VERSION 5.7 ;
  NOWIREEXTENSIONATPIN ON ;
  DIVIDERCHAR "/" ;
  BUSBITCHARS "[]" ;
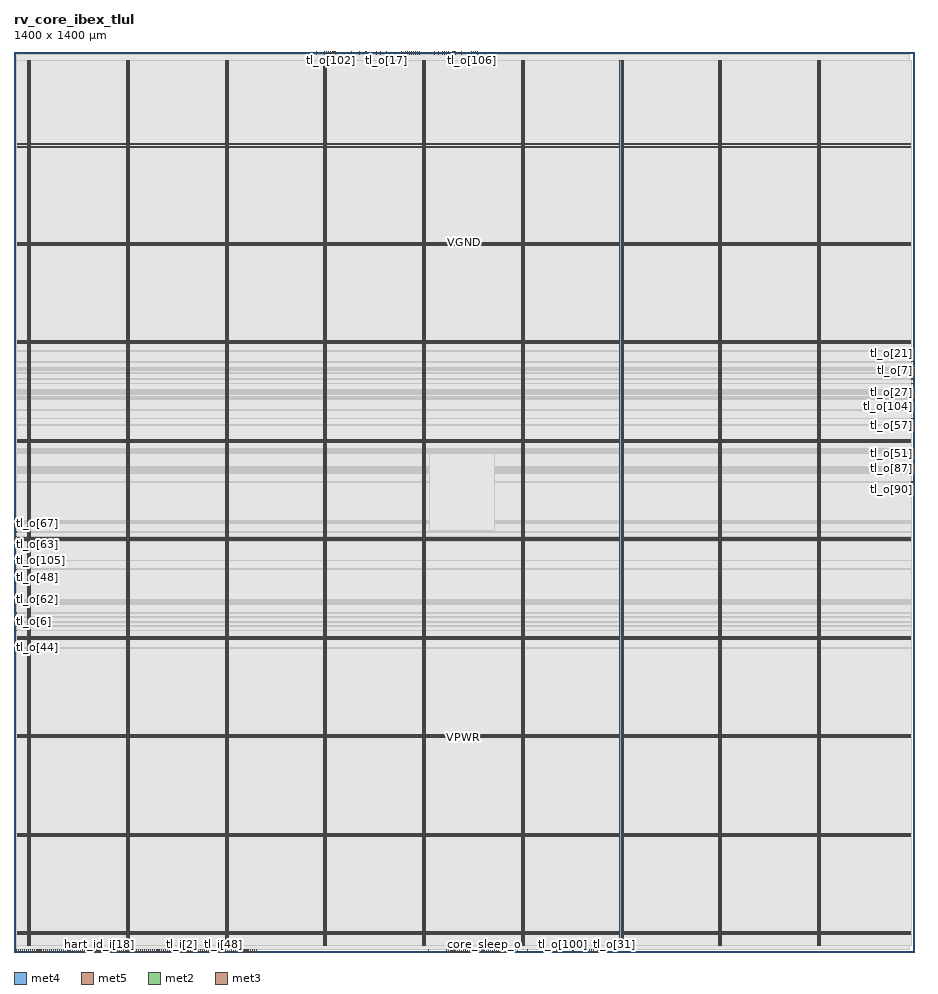
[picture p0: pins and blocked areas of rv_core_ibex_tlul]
MACRO rv_core_ibex_tlul
  CLASS BLOCK ;
  FOREIGN rv_core_ibex_tlul ;
  ORIGIN 0.000 0.000 ;
  SIZE 1400.000 BY 1400.000 ;
  PIN VGND
    DIRECTION INOUT ;
    USE GROUND ;
    PORT
      LAYER met4 ;
        RECT 24.340 10.640 25.940 1387.440 ;
    END
    PORT
      LAYER met4 ;
        RECT 177.940 10.640 179.540 1387.440 ;
    END
    PORT
      LAYER met4 ;
        RECT 331.540 10.640 333.140 1387.440 ;
    END
    PORT
      LAYER met4 ;
        RECT 485.140 10.640 486.740 1387.440 ;
    END
    PORT
      LAYER met4 ;
        RECT 638.740 10.640 640.340 1387.440 ;
    END
    PORT
      LAYER met4 ;
        RECT 792.340 10.640 793.940 1387.440 ;
    END
    PORT
      LAYER met4 ;
        RECT 945.940 10.640 947.540 1387.440 ;
    END
    PORT
      LAYER met4 ;
        RECT 1099.540 10.640 1101.140 1387.440 ;
    END
    PORT
      LAYER met4 ;
        RECT 1253.140 10.640 1254.740 1387.440 ;
    END
    PORT
      LAYER met5 ;
        RECT 5.280 30.030 1394.500 31.630 ;
    END
    PORT
      LAYER met5 ;
        RECT 5.280 183.210 1394.500 184.810 ;
    END
    PORT
      LAYER met5 ;
        RECT 5.280 336.390 1394.500 337.990 ;
    END
    PORT
      LAYER met5 ;
        RECT 5.280 489.570 1394.500 491.170 ;
    END
    PORT
      LAYER met5 ;
        RECT 5.280 642.750 1394.500 644.350 ;
    END
    PORT
      LAYER met5 ;
        RECT 5.280 795.930 1394.500 797.530 ;
    END
    PORT
      LAYER met5 ;
        RECT 5.280 949.110 1394.500 950.710 ;
    END
    PORT
      LAYER met5 ;
        RECT 5.280 1102.290 1394.500 1103.890 ;
    END
    PORT
      LAYER met5 ;
        RECT 5.280 1255.470 1394.500 1257.070 ;
    END
  END VGND
  PIN VPWR
    DIRECTION INOUT ;
    USE POWER ;
    PORT
      LAYER met4 ;
        RECT 21.040 10.640 22.640 1387.440 ;
    END
    PORT
      LAYER met4 ;
        RECT 174.640 10.640 176.240 1387.440 ;
    END
    PORT
      LAYER met4 ;
        RECT 328.240 10.640 329.840 1387.440 ;
    END
    PORT
      LAYER met4 ;
        RECT 481.840 10.640 483.440 1387.440 ;
    END
    PORT
      LAYER met4 ;
        RECT 635.440 10.640 637.040 1387.440 ;
    END
    PORT
      LAYER met4 ;
        RECT 789.040 10.640 790.640 1387.440 ;
    END
    PORT
      LAYER met4 ;
        RECT 942.640 10.640 944.240 1387.440 ;
    END
    PORT
      LAYER met4 ;
        RECT 1096.240 10.640 1097.840 1387.440 ;
    END
    PORT
      LAYER met4 ;
        RECT 1249.840 10.640 1251.440 1387.440 ;
    END
    PORT
      LAYER met5 ;
        RECT 5.280 26.730 1394.500 28.330 ;
    END
    PORT
      LAYER met5 ;
        RECT 5.280 179.910 1394.500 181.510 ;
    END
    PORT
      LAYER met5 ;
        RECT 5.280 333.090 1394.500 334.690 ;
    END
    PORT
      LAYER met5 ;
        RECT 5.280 486.270 1394.500 487.870 ;
    END
    PORT
      LAYER met5 ;
        RECT 5.280 639.450 1394.500 641.050 ;
    END
    PORT
      LAYER met5 ;
        RECT 5.280 792.630 1394.500 794.230 ;
    END
    PORT
      LAYER met5 ;
        RECT 5.280 945.810 1394.500 947.410 ;
    END
    PORT
      LAYER met5 ;
        RECT 5.280 1098.990 1394.500 1100.590 ;
    END
    PORT
      LAYER met5 ;
        RECT 5.280 1252.170 1394.500 1253.770 ;
    END
  END VPWR
  PIN boot_addr_i[0]
    DIRECTION INPUT ;
    USE SIGNAL ;
    PORT
      LAYER met2 ;
        RECT 0.090 0.000 0.370 4.000 ;
    END
  END boot_addr_i[0]
  PIN boot_addr_i[10]
    DIRECTION INPUT ;
    USE SIGNAL ;
    PORT
      LAYER met2 ;
        RECT 3.310 0.000 3.590 4.000 ;
    END
  END boot_addr_i[10]
  PIN boot_addr_i[11]
    DIRECTION INPUT ;
    USE SIGNAL ;
    PORT
      LAYER met2 ;
        RECT 6.530 0.000 6.810 4.000 ;
    END
  END boot_addr_i[11]
  PIN boot_addr_i[12]
    DIRECTION INPUT ;
    USE SIGNAL ;
    PORT
      LAYER met2 ;
        RECT 9.750 0.000 10.030 4.000 ;
    END
  END boot_addr_i[12]
  PIN boot_addr_i[13]
    DIRECTION INPUT ;
    USE SIGNAL ;
    PORT
      LAYER met2 ;
        RECT 12.970 0.000 13.250 4.000 ;
    END
  END boot_addr_i[13]
  PIN boot_addr_i[14]
    DIRECTION INPUT ;
    USE SIGNAL ;
    PORT
      LAYER met2 ;
        RECT 16.190 0.000 16.470 4.000 ;
    END
  END boot_addr_i[14]
  PIN boot_addr_i[15]
    DIRECTION INPUT ;
    USE SIGNAL ;
    PORT
      LAYER met2 ;
        RECT 19.410 0.000 19.690 4.000 ;
    END
  END boot_addr_i[15]
  PIN boot_addr_i[16]
    DIRECTION INPUT ;
    USE SIGNAL ;
    PORT
      LAYER met2 ;
        RECT 22.630 0.000 22.910 4.000 ;
    END
  END boot_addr_i[16]
  PIN boot_addr_i[17]
    DIRECTION INPUT ;
    USE SIGNAL ;
    PORT
      LAYER met2 ;
        RECT 25.850 0.000 26.130 4.000 ;
    END
  END boot_addr_i[17]
  PIN boot_addr_i[18]
    DIRECTION INPUT ;
    USE SIGNAL ;
    PORT
      LAYER met2 ;
        RECT 29.070 0.000 29.350 4.000 ;
    END
  END boot_addr_i[18]
  PIN boot_addr_i[19]
    DIRECTION INPUT ;
    USE SIGNAL ;
    PORT
      LAYER met2 ;
        RECT 32.290 0.000 32.570 4.000 ;
    END
  END boot_addr_i[19]
  PIN boot_addr_i[1]
    DIRECTION INPUT ;
    USE SIGNAL ;
    PORT
      LAYER met2 ;
        RECT 35.510 0.000 35.790 4.000 ;
    END
  END boot_addr_i[1]
  PIN boot_addr_i[20]
    DIRECTION INPUT ;
    USE SIGNAL ;
    PORT
      LAYER met2 ;
        RECT 38.730 0.000 39.010 4.000 ;
    END
  END boot_addr_i[20]
  PIN boot_addr_i[21]
    DIRECTION INPUT ;
    USE SIGNAL ;
    PORT
      LAYER met2 ;
        RECT 41.950 0.000 42.230 4.000 ;
    END
  END boot_addr_i[21]
  PIN boot_addr_i[22]
    DIRECTION INPUT ;
    USE SIGNAL ;
    PORT
      LAYER met2 ;
        RECT 45.170 0.000 45.450 4.000 ;
    END
  END boot_addr_i[22]
  PIN boot_addr_i[23]
    DIRECTION INPUT ;
    USE SIGNAL ;
    PORT
      LAYER met2 ;
        RECT 48.390 0.000 48.670 4.000 ;
    END
  END boot_addr_i[23]
  PIN boot_addr_i[24]
    DIRECTION INPUT ;
    USE SIGNAL ;
    PORT
      LAYER met2 ;
        RECT 51.610 0.000 51.890 4.000 ;
    END
  END boot_addr_i[24]
  PIN boot_addr_i[25]
    DIRECTION INPUT ;
    USE SIGNAL ;
    PORT
      LAYER met2 ;
        RECT 54.830 0.000 55.110 4.000 ;
    END
  END boot_addr_i[25]
  PIN boot_addr_i[26]
    DIRECTION INPUT ;
    USE SIGNAL ;
    PORT
      LAYER met2 ;
        RECT 58.050 0.000 58.330 4.000 ;
    END
  END boot_addr_i[26]
  PIN boot_addr_i[27]
    DIRECTION INPUT ;
    USE SIGNAL ;
    PORT
      LAYER met2 ;
        RECT 61.270 0.000 61.550 4.000 ;
    END
  END boot_addr_i[27]
  PIN boot_addr_i[28]
    DIRECTION INPUT ;
    USE SIGNAL ;
    PORT
      LAYER met2 ;
        RECT 64.490 0.000 64.770 4.000 ;
    END
  END boot_addr_i[28]
  PIN boot_addr_i[29]
    DIRECTION INPUT ;
    USE SIGNAL ;
    PORT
      LAYER met2 ;
        RECT 67.710 0.000 67.990 4.000 ;
    END
  END boot_addr_i[29]
  PIN boot_addr_i[2]
    DIRECTION INPUT ;
    USE SIGNAL ;
    PORT
      LAYER met2 ;
        RECT 70.930 0.000 71.210 4.000 ;
    END
  END boot_addr_i[2]
  PIN boot_addr_i[30]
    DIRECTION INPUT ;
    USE SIGNAL ;
    PORT
      LAYER met2 ;
        RECT 74.150 0.000 74.430 4.000 ;
    END
  END boot_addr_i[30]
  PIN boot_addr_i[31]
    DIRECTION INPUT ;
    USE SIGNAL ;
    PORT
      LAYER met2 ;
        RECT 77.370 0.000 77.650 4.000 ;
    END
  END boot_addr_i[31]
  PIN boot_addr_i[3]
    DIRECTION INPUT ;
    USE SIGNAL ;
    PORT
      LAYER met2 ;
        RECT 80.590 0.000 80.870 4.000 ;
    END
  END boot_addr_i[3]
  PIN boot_addr_i[4]
    DIRECTION INPUT ;
    USE SIGNAL ;
    PORT
      LAYER met2 ;
        RECT 83.810 0.000 84.090 4.000 ;
    END
  END boot_addr_i[4]
  PIN boot_addr_i[5]
    DIRECTION INPUT ;
    USE SIGNAL ;
    PORT
      LAYER met2 ;
        RECT 87.030 0.000 87.310 4.000 ;
    END
  END boot_addr_i[5]
  PIN boot_addr_i[6]
    DIRECTION INPUT ;
    USE SIGNAL ;
    PORT
      LAYER met2 ;
        RECT 90.250 0.000 90.530 4.000 ;
    END
  END boot_addr_i[6]
  PIN boot_addr_i[7]
    DIRECTION INPUT ;
    USE SIGNAL ;
    PORT
      LAYER met2 ;
        RECT 93.470 0.000 93.750 4.000 ;
    END
  END boot_addr_i[7]
  PIN boot_addr_i[8]
    DIRECTION INPUT ;
    USE SIGNAL ;
    PORT
      LAYER met2 ;
        RECT 96.690 0.000 96.970 4.000 ;
    END
  END boot_addr_i[8]
  PIN boot_addr_i[9]
    DIRECTION INPUT ;
    USE SIGNAL ;
    PORT
      LAYER met2 ;
        RECT 99.910 0.000 100.190 4.000 ;
    END
  END boot_addr_i[9]
  PIN clk_i
    DIRECTION INPUT ;
    USE SIGNAL ;
    ANTENNAGATEAREA 1.286700 ;
    ANTENNADIFFAREA 0.434700 ;
    PORT
      LAYER met2 ;
        RECT 782.550 0.000 782.830 4.000 ;
    END
  END clk_i
  PIN core_sleep_o
    DIRECTION OUTPUT ;
    USE SIGNAL ;
    ANTENNADIFFAREA 0.445500 ;
    PORT
      LAYER met2 ;
        RECT 731.030 0.000 731.310 4.000 ;
    END
  END core_sleep_o
  PIN hart_id_i[0]
    DIRECTION INPUT ;
    USE SIGNAL ;
    PORT
      LAYER met2 ;
        RECT 103.130 0.000 103.410 4.000 ;
    END
  END hart_id_i[0]
  PIN hart_id_i[10]
    DIRECTION INPUT ;
    USE SIGNAL ;
    PORT
      LAYER met2 ;
        RECT 106.350 0.000 106.630 4.000 ;
    END
  END hart_id_i[10]
  PIN hart_id_i[11]
    DIRECTION INPUT ;
    USE SIGNAL ;
    PORT
      LAYER met2 ;
        RECT 109.570 0.000 109.850 4.000 ;
    END
  END hart_id_i[11]
  PIN hart_id_i[12]
    DIRECTION INPUT ;
    USE SIGNAL ;
    PORT
      LAYER met2 ;
        RECT 112.790 0.000 113.070 4.000 ;
    END
  END hart_id_i[12]
  PIN hart_id_i[13]
    DIRECTION INPUT ;
    USE SIGNAL ;
    PORT
      LAYER met2 ;
        RECT 116.010 0.000 116.290 4.000 ;
    END
  END hart_id_i[13]
  PIN hart_id_i[14]
    DIRECTION INPUT ;
    USE SIGNAL ;
    PORT
      LAYER met2 ;
        RECT 119.230 0.000 119.510 4.000 ;
    END
  END hart_id_i[14]
  PIN hart_id_i[15]
    DIRECTION INPUT ;
    USE SIGNAL ;
    PORT
      LAYER met2 ;
        RECT 122.450 0.000 122.730 4.000 ;
    END
  END hart_id_i[15]
  PIN hart_id_i[16]
    DIRECTION INPUT ;
    USE SIGNAL ;
    PORT
      LAYER met2 ;
        RECT 125.670 0.000 125.950 4.000 ;
    END
  END hart_id_i[16]
  PIN hart_id_i[17]
    DIRECTION INPUT ;
    USE SIGNAL ;
    PORT
      LAYER met2 ;
        RECT 128.890 0.000 129.170 4.000 ;
    END
  END hart_id_i[17]
  PIN hart_id_i[18]
    DIRECTION INPUT ;
    USE SIGNAL ;
    PORT
      LAYER met2 ;
        RECT 132.110 0.000 132.390 4.000 ;
    END
  END hart_id_i[18]
  PIN hart_id_i[19]
    DIRECTION INPUT ;
    USE SIGNAL ;
    PORT
      LAYER met2 ;
        RECT 135.330 0.000 135.610 4.000 ;
    END
  END hart_id_i[19]
  PIN hart_id_i[1]
    DIRECTION INPUT ;
    USE SIGNAL ;
    PORT
      LAYER met2 ;
        RECT 138.550 0.000 138.830 4.000 ;
    END
  END hart_id_i[1]
  PIN hart_id_i[20]
    DIRECTION INPUT ;
    USE SIGNAL ;
    PORT
      LAYER met2 ;
        RECT 141.770 0.000 142.050 4.000 ;
    END
  END hart_id_i[20]
  PIN hart_id_i[21]
    DIRECTION INPUT ;
    USE SIGNAL ;
    PORT
      LAYER met2 ;
        RECT 144.990 0.000 145.270 4.000 ;
    END
  END hart_id_i[21]
  PIN hart_id_i[22]
    DIRECTION INPUT ;
    USE SIGNAL ;
    PORT
      LAYER met2 ;
        RECT 148.210 0.000 148.490 4.000 ;
    END
  END hart_id_i[22]
  PIN hart_id_i[23]
    DIRECTION INPUT ;
    USE SIGNAL ;
    PORT
      LAYER met2 ;
        RECT 151.430 0.000 151.710 4.000 ;
    END
  END hart_id_i[23]
  PIN hart_id_i[24]
    DIRECTION INPUT ;
    USE SIGNAL ;
    PORT
      LAYER met2 ;
        RECT 154.650 0.000 154.930 4.000 ;
    END
  END hart_id_i[24]
  PIN hart_id_i[25]
    DIRECTION INPUT ;
    USE SIGNAL ;
    PORT
      LAYER met2 ;
        RECT 157.870 0.000 158.150 4.000 ;
    END
  END hart_id_i[25]
  PIN hart_id_i[26]
    DIRECTION INPUT ;
    USE SIGNAL ;
    PORT
      LAYER met2 ;
        RECT 161.090 0.000 161.370 4.000 ;
    END
  END hart_id_i[26]
  PIN hart_id_i[27]
    DIRECTION INPUT ;
    USE SIGNAL ;
    PORT
      LAYER met2 ;
        RECT 164.310 0.000 164.590 4.000 ;
    END
  END hart_id_i[27]
  PIN hart_id_i[28]
    DIRECTION INPUT ;
    USE SIGNAL ;
    PORT
      LAYER met2 ;
        RECT 167.530 0.000 167.810 4.000 ;
    END
  END hart_id_i[28]
  PIN hart_id_i[29]
    DIRECTION INPUT ;
    USE SIGNAL ;
    PORT
      LAYER met2 ;
        RECT 170.750 0.000 171.030 4.000 ;
    END
  END hart_id_i[29]
  PIN hart_id_i[2]
    DIRECTION INPUT ;
    USE SIGNAL ;
    PORT
      LAYER met2 ;
        RECT 173.970 0.000 174.250 4.000 ;
    END
  END hart_id_i[2]
  PIN hart_id_i[30]
    DIRECTION INPUT ;
    USE SIGNAL ;
    PORT
      LAYER met2 ;
        RECT 177.190 0.000 177.470 4.000 ;
    END
  END hart_id_i[30]
  PIN hart_id_i[31]
    DIRECTION INPUT ;
    USE SIGNAL ;
    PORT
      LAYER met2 ;
        RECT 180.410 0.000 180.690 4.000 ;
    END
  END hart_id_i[31]
  PIN hart_id_i[3]
    DIRECTION INPUT ;
    USE SIGNAL ;
    PORT
      LAYER met2 ;
        RECT 183.630 0.000 183.910 4.000 ;
    END
  END hart_id_i[3]
  PIN hart_id_i[4]
    DIRECTION INPUT ;
    USE SIGNAL ;
    PORT
      LAYER met2 ;
        RECT 186.850 0.000 187.130 4.000 ;
    END
  END hart_id_i[4]
  PIN hart_id_i[5]
    DIRECTION INPUT ;
    USE SIGNAL ;
    PORT
      LAYER met2 ;
        RECT 190.070 0.000 190.350 4.000 ;
    END
  END hart_id_i[5]
  PIN hart_id_i[6]
    DIRECTION INPUT ;
    USE SIGNAL ;
    PORT
      LAYER met2 ;
        RECT 193.290 0.000 193.570 4.000 ;
    END
  END hart_id_i[6]
  PIN hart_id_i[7]
    DIRECTION INPUT ;
    USE SIGNAL ;
    PORT
      LAYER met2 ;
        RECT 196.510 0.000 196.790 4.000 ;
    END
  END hart_id_i[7]
  PIN hart_id_i[8]
    DIRECTION INPUT ;
    USE SIGNAL ;
    PORT
      LAYER met2 ;
        RECT 199.730 0.000 200.010 4.000 ;
    END
  END hart_id_i[8]
  PIN hart_id_i[9]
    DIRECTION INPUT ;
    USE SIGNAL ;
    PORT
      LAYER met2 ;
        RECT 202.950 0.000 203.230 4.000 ;
    END
  END hart_id_i[9]
  PIN irq_external_i
    DIRECTION INPUT ;
    USE SIGNAL ;
    PORT
      LAYER met2 ;
        RECT 206.170 0.000 206.450 4.000 ;
    END
  END irq_external_i
  PIN irq_software_i
    DIRECTION INPUT ;
    USE SIGNAL ;
    PORT
      LAYER met2 ;
        RECT 209.390 0.000 209.670 4.000 ;
    END
  END irq_software_i
  PIN irq_timer_i
    DIRECTION INPUT ;
    USE SIGNAL ;
    PORT
      LAYER met2 ;
        RECT 212.610 0.000 212.890 4.000 ;
    END
  END irq_timer_i
  PIN rst_ni
    DIRECTION INPUT ;
    USE SIGNAL ;
    ANTENNAGATEAREA 0.682200 ;
    ANTENNADIFFAREA 0.434700 ;
    PORT
      LAYER met2 ;
        RECT 644.090 0.000 644.370 4.000 ;
    END
  END rst_ni
  PIN tl_i[0]
    DIRECTION INPUT ;
    USE SIGNAL ;
    ANTENNAGATEAREA 0.682200 ;
    ANTENNADIFFAREA 0.434700 ;
    PORT
      LAYER met2 ;
        RECT 679.510 0.000 679.790 4.000 ;
    END
  END tl_i[0]
  PIN tl_i[10]
    DIRECTION INPUT ;
    USE SIGNAL ;
    ANTENNAGATEAREA 0.631200 ;
    ANTENNADIFFAREA 0.434700 ;
    PORT
      LAYER met2 ;
        RECT 698.830 0.000 699.110 4.000 ;
    END
  END tl_i[10]
  PIN tl_i[11]
    DIRECTION INPUT ;
    USE SIGNAL ;
    ANTENNAGATEAREA 0.631200 ;
    ANTENNADIFFAREA 0.434700 ;
    PORT
      LAYER met2 ;
        RECT 714.930 0.000 715.210 4.000 ;
    END
  END tl_i[11]
  PIN tl_i[12]
    DIRECTION INPUT ;
    USE SIGNAL ;
    ANTENNAGATEAREA 0.631200 ;
    ANTENNADIFFAREA 0.434700 ;
    PORT
      LAYER met2 ;
        RECT 705.270 0.000 705.550 4.000 ;
    END
  END tl_i[12]
  PIN tl_i[13]
    DIRECTION INPUT ;
    USE SIGNAL ;
    ANTENNAGATEAREA 0.631200 ;
    ANTENNADIFFAREA 0.434700 ;
    PORT
      LAYER met2 ;
        RECT 727.810 0.000 728.090 4.000 ;
    END
  END tl_i[13]
  PIN tl_i[14]
    DIRECTION INPUT ;
    USE SIGNAL ;
    ANTENNAGATEAREA 0.631200 ;
    ANTENNADIFFAREA 0.434700 ;
    PORT
      LAYER met2 ;
        RECT 779.330 0.000 779.610 4.000 ;
    END
  END tl_i[14]
  PIN tl_i[15]
    DIRECTION INPUT ;
    USE SIGNAL ;
    ANTENNAGATEAREA 0.631200 ;
    ANTENNADIFFAREA 0.434700 ;
    PORT
      LAYER met2 ;
        RECT 743.910 0.000 744.190 4.000 ;
    END
  END tl_i[15]
  PIN tl_i[16]
    DIRECTION INPUT ;
    USE SIGNAL ;
    PORT
      LAYER met2 ;
        RECT 215.830 0.000 216.110 4.000 ;
    END
  END tl_i[16]
  PIN tl_i[17]
    DIRECTION INPUT ;
    USE SIGNAL ;
    PORT
      LAYER met2 ;
        RECT 219.050 0.000 219.330 4.000 ;
    END
  END tl_i[17]
  PIN tl_i[18]
    DIRECTION INPUT ;
    USE SIGNAL ;
    PORT
      LAYER met2 ;
        RECT 222.270 0.000 222.550 4.000 ;
    END
  END tl_i[18]
  PIN tl_i[19]
    DIRECTION INPUT ;
    USE SIGNAL ;
    PORT
      LAYER met2 ;
        RECT 225.490 0.000 225.770 4.000 ;
    END
  END tl_i[19]
  PIN tl_i[1]
    DIRECTION INPUT ;
    USE SIGNAL ;
    ANTENNAGATEAREA 0.860700 ;
    ANTENNADIFFAREA 0.434700 ;
    PORT
      LAYER met2 ;
        RECT 718.150 0.000 718.430 4.000 ;
    END
  END tl_i[1]
  PIN tl_i[20]
    DIRECTION INPUT ;
    USE SIGNAL ;
    PORT
      LAYER met2 ;
        RECT 228.710 0.000 228.990 4.000 ;
    END
  END tl_i[20]
  PIN tl_i[21]
    DIRECTION INPUT ;
    USE SIGNAL ;
    PORT
      LAYER met2 ;
        RECT 231.930 0.000 232.210 4.000 ;
    END
  END tl_i[21]
  PIN tl_i[22]
    DIRECTION INPUT ;
    USE SIGNAL ;
    PORT
      LAYER met2 ;
        RECT 235.150 0.000 235.430 4.000 ;
    END
  END tl_i[22]
  PIN tl_i[23]
    DIRECTION INPUT ;
    USE SIGNAL ;
    PORT
      LAYER met2 ;
        RECT 238.370 0.000 238.650 4.000 ;
    END
  END tl_i[23]
  PIN tl_i[24]
    DIRECTION INPUT ;
    USE SIGNAL ;
    PORT
      LAYER met2 ;
        RECT 241.590 0.000 241.870 4.000 ;
    END
  END tl_i[24]
  PIN tl_i[25]
    DIRECTION INPUT ;
    USE SIGNAL ;
    PORT
      LAYER met2 ;
        RECT 244.810 0.000 245.090 4.000 ;
    END
  END tl_i[25]
  PIN tl_i[26]
    DIRECTION INPUT ;
    USE SIGNAL ;
    PORT
      LAYER met2 ;
        RECT 248.030 0.000 248.310 4.000 ;
    END
  END tl_i[26]
  PIN tl_i[27]
    DIRECTION INPUT ;
    USE SIGNAL ;
    PORT
      LAYER met2 ;
        RECT 251.250 0.000 251.530 4.000 ;
    END
  END tl_i[27]
  PIN tl_i[28]
    DIRECTION INPUT ;
    USE SIGNAL ;
    PORT
      LAYER met2 ;
        RECT 254.470 0.000 254.750 4.000 ;
    END
  END tl_i[28]
  PIN tl_i[29]
    DIRECTION INPUT ;
    USE SIGNAL ;
    PORT
      LAYER met2 ;
        RECT 257.690 0.000 257.970 4.000 ;
    END
  END tl_i[29]
  PIN tl_i[2]
    DIRECTION INPUT ;
    USE SIGNAL ;
    PORT
      LAYER met2 ;
        RECT 260.910 0.000 261.190 4.000 ;
    END
  END tl_i[2]
  PIN tl_i[30]
    DIRECTION INPUT ;
    USE SIGNAL ;
    PORT
      LAYER met2 ;
        RECT 264.130 0.000 264.410 4.000 ;
    END
  END tl_i[30]
  PIN tl_i[31]
    DIRECTION INPUT ;
    USE SIGNAL ;
    PORT
      LAYER met2 ;
        RECT 267.350 0.000 267.630 4.000 ;
    END
  END tl_i[31]
  PIN tl_i[32]
    DIRECTION INPUT ;
    USE SIGNAL ;
    PORT
      LAYER met2 ;
        RECT 270.570 0.000 270.850 4.000 ;
    END
  END tl_i[32]
  PIN tl_i[33]
    DIRECTION INPUT ;
    USE SIGNAL ;
    PORT
      LAYER met2 ;
        RECT 273.790 0.000 274.070 4.000 ;
    END
  END tl_i[33]
  PIN tl_i[34]
    DIRECTION INPUT ;
    USE SIGNAL ;
    PORT
      LAYER met2 ;
        RECT 277.010 0.000 277.290 4.000 ;
    END
  END tl_i[34]
  PIN tl_i[35]
    DIRECTION INPUT ;
    USE SIGNAL ;
    PORT
      LAYER met2 ;
        RECT 280.230 0.000 280.510 4.000 ;
    END
  END tl_i[35]
  PIN tl_i[36]
    DIRECTION INPUT ;
    USE SIGNAL ;
    PORT
      LAYER met2 ;
        RECT 283.450 0.000 283.730 4.000 ;
    END
  END tl_i[36]
  PIN tl_i[37]
    DIRECTION INPUT ;
    USE SIGNAL ;
    PORT
      LAYER met2 ;
        RECT 286.670 0.000 286.950 4.000 ;
    END
  END tl_i[37]
  PIN tl_i[38]
    DIRECTION INPUT ;
    USE SIGNAL ;
    PORT
      LAYER met2 ;
        RECT 289.890 0.000 290.170 4.000 ;
    END
  END tl_i[38]
  PIN tl_i[39]
    DIRECTION INPUT ;
    USE SIGNAL ;
    PORT
      LAYER met2 ;
        RECT 293.110 0.000 293.390 4.000 ;
    END
  END tl_i[39]
  PIN tl_i[3]
    DIRECTION INPUT ;
    USE SIGNAL ;
    PORT
      LAYER met2 ;
        RECT 296.330 0.000 296.610 4.000 ;
    END
  END tl_i[3]
  PIN tl_i[40]
    DIRECTION INPUT ;
    USE SIGNAL ;
    PORT
      LAYER met2 ;
        RECT 299.550 0.000 299.830 4.000 ;
    END
  END tl_i[40]
  PIN tl_i[41]
    DIRECTION INPUT ;
    USE SIGNAL ;
    PORT
      LAYER met2 ;
        RECT 302.770 0.000 303.050 4.000 ;
    END
  END tl_i[41]
  PIN tl_i[42]
    DIRECTION INPUT ;
    USE SIGNAL ;
    PORT
      LAYER met2 ;
        RECT 305.990 0.000 306.270 4.000 ;
    END
  END tl_i[42]
  PIN tl_i[43]
    DIRECTION INPUT ;
    USE SIGNAL ;
    PORT
      LAYER met2 ;
        RECT 309.210 0.000 309.490 4.000 ;
    END
  END tl_i[43]
  PIN tl_i[44]
    DIRECTION INPUT ;
    USE SIGNAL ;
    PORT
      LAYER met2 ;
        RECT 312.430 0.000 312.710 4.000 ;
    END
  END tl_i[44]
  PIN tl_i[45]
    DIRECTION INPUT ;
    USE SIGNAL ;
    PORT
      LAYER met2 ;
        RECT 315.650 0.000 315.930 4.000 ;
    END
  END tl_i[45]
  PIN tl_i[46]
    DIRECTION INPUT ;
    USE SIGNAL ;
    PORT
      LAYER met2 ;
        RECT 318.870 0.000 319.150 4.000 ;
    END
  END tl_i[46]
  PIN tl_i[47]
    DIRECTION INPUT ;
    USE SIGNAL ;
    PORT
      LAYER met2 ;
        RECT 322.090 0.000 322.370 4.000 ;
    END
  END tl_i[47]
  PIN tl_i[48]
    DIRECTION INPUT ;
    USE SIGNAL ;
    PORT
      LAYER met2 ;
        RECT 325.310 0.000 325.590 4.000 ;
    END
  END tl_i[48]
  PIN tl_i[49]
    DIRECTION INPUT ;
    USE SIGNAL ;
    PORT
      LAYER met2 ;
        RECT 328.530 0.000 328.810 4.000 ;
    END
  END tl_i[49]
  PIN tl_i[4]
    DIRECTION INPUT ;
    USE SIGNAL ;
    PORT
      LAYER met2 ;
        RECT 331.750 0.000 332.030 4.000 ;
    END
  END tl_i[4]
  PIN tl_i[50]
    DIRECTION INPUT ;
    USE SIGNAL ;
    PORT
      LAYER met2 ;
        RECT 334.970 0.000 335.250 4.000 ;
    END
  END tl_i[50]
  PIN tl_i[51]
    DIRECTION INPUT ;
    USE SIGNAL ;
    PORT
      LAYER met2 ;
        RECT 338.190 0.000 338.470 4.000 ;
    END
  END tl_i[51]
  PIN tl_i[52]
    DIRECTION INPUT ;
    USE SIGNAL ;
    PORT
      LAYER met2 ;
        RECT 341.410 0.000 341.690 4.000 ;
    END
  END tl_i[52]
  PIN tl_i[53]
    DIRECTION INPUT ;
    USE SIGNAL ;
    PORT
      LAYER met2 ;
        RECT 344.630 0.000 344.910 4.000 ;
    END
  END tl_i[53]
  PIN tl_i[54]
    DIRECTION INPUT ;
    USE SIGNAL ;
    PORT
      LAYER met2 ;
        RECT 347.850 0.000 348.130 4.000 ;
    END
  END tl_i[54]
  PIN tl_i[55]
    DIRECTION INPUT ;
    USE SIGNAL ;
    PORT
      LAYER met2 ;
        RECT 351.070 0.000 351.350 4.000 ;
    END
  END tl_i[55]
  PIN tl_i[56]
    DIRECTION INPUT ;
    USE SIGNAL ;
    PORT
      LAYER met2 ;
        RECT 354.290 0.000 354.570 4.000 ;
    END
  END tl_i[56]
  PIN tl_i[57]
    DIRECTION INPUT ;
    USE SIGNAL ;
    ANTENNAGATEAREA 0.631200 ;
    ANTENNADIFFAREA 0.434700 ;
    PORT
      LAYER met2 ;
        RECT 711.710 0.000 711.990 4.000 ;
    END
  END tl_i[57]
  PIN tl_i[58]
    DIRECTION INPUT ;
    USE SIGNAL ;
    ANTENNAGATEAREA 0.631200 ;
    ANTENNADIFFAREA 0.434700 ;
    PORT
      LAYER met2 ;
        RECT 734.250 0.000 734.530 4.000 ;
    END
  END tl_i[58]
  PIN tl_i[59]
    DIRECTION INPUT ;
    USE SIGNAL ;
    PORT
      LAYER met2 ;
        RECT 357.510 0.000 357.790 4.000 ;
    END
  END tl_i[59]
  PIN tl_i[5]
    DIRECTION INPUT ;
    USE SIGNAL ;
    PORT
      LAYER met2 ;
        RECT 360.730 0.000 361.010 4.000 ;
    END
  END tl_i[5]
  PIN tl_i[60]
    DIRECTION INPUT ;
    USE SIGNAL ;
    PORT
      LAYER met2 ;
        RECT 363.950 0.000 364.230 4.000 ;
    END
  END tl_i[60]
  PIN tl_i[61]
    DIRECTION INPUT ;
    USE SIGNAL ;
    PORT
      LAYER met2 ;
        RECT 367.170 0.000 367.450 4.000 ;
    END
  END tl_i[61]
  PIN tl_i[62]
    DIRECTION INPUT ;
    USE SIGNAL ;
    ANTENNAGATEAREA 0.560700 ;
    ANTENNADIFFAREA 0.434700 ;
    PORT
      LAYER met2 ;
        RECT 747.130 0.000 747.410 4.000 ;
    END
  END tl_i[62]
  PIN tl_i[63]
    DIRECTION INPUT ;
    USE SIGNAL ;
    ANTENNAGATEAREA 0.631200 ;
    ANTENNADIFFAREA 0.434700 ;
    PORT
      LAYER met2 ;
        RECT 737.470 0.000 737.750 4.000 ;
    END
  END tl_i[63]
  PIN tl_i[64]
    DIRECTION INPUT ;
    USE SIGNAL ;
    ANTENNAGATEAREA 0.560700 ;
    ANTENNADIFFAREA 0.434700 ;
    PORT
      LAYER met2 ;
        RECT 708.490 0.000 708.770 4.000 ;
    END
  END tl_i[64]
  PIN tl_i[65]
    DIRECTION INPUT ;
    USE SIGNAL ;
    ANTENNAGATEAREA 0.860700 ;
    ANTENNADIFFAREA 0.434700 ;
    PORT
      LAYER met2 ;
        RECT 692.390 0.000 692.670 4.000 ;
    END
  END tl_i[65]
  PIN tl_i[6]
    DIRECTION INPUT ;
    USE SIGNAL ;
    PORT
      LAYER met2 ;
        RECT 370.390 0.000 370.670 4.000 ;
    END
  END tl_i[6]
  PIN tl_i[7]
    DIRECTION INPUT ;
    USE SIGNAL ;
    PORT
      LAYER met2 ;
        RECT 373.610 0.000 373.890 4.000 ;
    END
  END tl_i[7]
  PIN tl_i[8]
    DIRECTION INPUT ;
    USE SIGNAL ;
    PORT
      LAYER met2 ;
        RECT 376.830 0.000 377.110 4.000 ;
    END
  END tl_i[8]
  PIN tl_i[9]
    DIRECTION INPUT ;
    USE SIGNAL ;
    ANTENNAGATEAREA 0.631200 ;
    ANTENNADIFFAREA 0.434700 ;
    PORT
      LAYER met2 ;
        RECT 702.050 0.000 702.330 4.000 ;
    END
  END tl_i[9]
  PIN tl_o[0]
    DIRECTION OUTPUT ;
    USE SIGNAL ;
    PORT
      LAYER met2 ;
        RECT 483.090 1396.000 483.370 1400.000 ;
    END
  END tl_o[0]
  PIN tl_o[100]
    DIRECTION OUTPUT ;
    USE SIGNAL ;
    PORT
      LAYER met2 ;
        RECT 853.390 0.000 853.670 4.000 ;
    END
  END tl_o[100]
  PIN tl_o[101]
    DIRECTION OUTPUT ;
    USE SIGNAL ;
    PORT
      LAYER met2 ;
        RECT 682.730 0.000 683.010 4.000 ;
    END
  END tl_o[101]
  PIN tl_o[102]
    DIRECTION OUTPUT ;
    USE SIGNAL ;
    PORT
      LAYER met2 ;
        RECT 492.750 1396.000 493.030 1400.000 ;
    END
  END tl_o[102]
  PIN tl_o[103]
    DIRECTION OUTPUT ;
    USE SIGNAL ;
    PORT
      LAYER met2 ;
        RECT 901.690 0.000 901.970 4.000 ;
    END
  END tl_o[103]
  PIN tl_o[104]
    DIRECTION OUTPUT ;
    USE SIGNAL ;
    PORT
      LAYER met3 ;
        RECT 1396.000 860.240 1400.000 860.840 ;
    END
  END tl_o[104]
  PIN tl_o[105]
    DIRECTION OUTPUT ;
    USE SIGNAL ;
    PORT
      LAYER met3 ;
        RECT 0.000 608.640 4.000 609.240 ;
    END
  END tl_o[105]
  PIN tl_o[106]
    DIRECTION OUTPUT ;
    USE SIGNAL ;
    PORT
      LAYER met2 ;
        RECT 711.710 1396.000 711.990 1400.000 ;
    END
  END tl_o[106]
  PIN tl_o[107]
    DIRECTION OUTPUT ;
    USE SIGNAL ;
    PORT
      LAYER met2 ;
        RECT 914.570 0.000 914.850 4.000 ;
    END
  END tl_o[107]
  PIN tl_o[108]
    DIRECTION OUTPUT ;
    USE SIGNAL ;
    PORT
      LAYER met3 ;
        RECT 0.000 527.040 4.000 527.640 ;
    END
  END tl_o[108]
  PIN tl_o[109]
    DIRECTION OUTPUT ;
    USE SIGNAL ;
    ANTENNADIFFAREA 0.445500 ;
    PORT
      LAYER met2 ;
        RECT 689.170 0.000 689.450 4.000 ;
    END
  END tl_o[109]
  PIN tl_o[10]
    DIRECTION OUTPUT ;
    USE SIGNAL ;
    ANTENNADIFFAREA 0.445500 ;
    PORT
      LAYER met2 ;
        RECT 685.950 1396.000 686.230 1400.000 ;
    END
  END tl_o[10]
  PIN tl_o[11]
    DIRECTION OUTPUT ;
    USE SIGNAL ;
    ANTENNADIFFAREA 0.445500 ;
    PORT
      LAYER met2 ;
        RECT 718.150 1396.000 718.430 1400.000 ;
    END
  END tl_o[11]
  PIN tl_o[12]
    DIRECTION OUTPUT ;
    USE SIGNAL ;
    ANTENNADIFFAREA 0.445500 ;
    PORT
      LAYER met2 ;
        RECT 682.730 1396.000 683.010 1400.000 ;
    END
  END tl_o[12]
  PIN tl_o[13]
    DIRECTION OUTPUT ;
    USE SIGNAL ;
    ANTENNADIFFAREA 0.445500 ;
    PORT
      LAYER met2 ;
        RECT 756.790 0.000 757.070 4.000 ;
    END
  END tl_o[13]
  PIN tl_o[14]
    DIRECTION OUTPUT ;
    USE SIGNAL ;
    ANTENNADIFFAREA 0.445500 ;
    PORT
      LAYER met2 ;
        RECT 695.610 1396.000 695.890 1400.000 ;
    END
  END tl_o[14]
  PIN tl_o[15]
    DIRECTION OUTPUT ;
    USE SIGNAL ;
    PORT
      LAYER met2 ;
        RECT 695.610 0.000 695.890 4.000 ;
    END
  END tl_o[15]
  PIN tl_o[16]
    DIRECTION OUTPUT ;
    USE SIGNAL ;
    PORT
      LAYER met2 ;
        RECT 850.170 0.000 850.450 4.000 ;
    END
  END tl_o[16]
  PIN tl_o[17]
    DIRECTION OUTPUT ;
    USE SIGNAL ;
    PORT
      LAYER met2 ;
        RECT 579.690 1396.000 579.970 1400.000 ;
    END
  END tl_o[17]
  PIN tl_o[18]
    DIRECTION OUTPUT ;
    USE SIGNAL ;
    PORT
      LAYER met3 ;
        RECT 0.000 544.040 4.000 544.640 ;
    END
  END tl_o[18]
  PIN tl_o[19]
    DIRECTION OUTPUT ;
    USE SIGNAL ;
    PORT
      LAYER met3 ;
        RECT 0.000 506.640 4.000 507.240 ;
    END
  END tl_o[19]
  PIN tl_o[1]
    DIRECTION OUTPUT ;
    USE SIGNAL ;
    PORT
      LAYER met2 ;
        RECT 898.470 0.000 898.750 4.000 ;
    END
  END tl_o[1]
  PIN tl_o[20]
    DIRECTION OUTPUT ;
    USE SIGNAL ;
    PORT
      LAYER met3 ;
        RECT 1396.000 873.840 1400.000 874.440 ;
    END
  END tl_o[20]
  PIN tl_o[21]
    DIRECTION OUTPUT ;
    USE SIGNAL ;
    PORT
      LAYER met3 ;
        RECT 1396.000 918.040 1400.000 918.640 ;
    END
  END tl_o[21]
  PIN tl_o[22]
    DIRECTION OUTPUT ;
    USE SIGNAL ;
    PORT
      LAYER met2 ;
        RECT 908.130 0.000 908.410 4.000 ;
    END
  END tl_o[22]
  PIN tl_o[23]
    DIRECTION OUTPUT ;
    USE SIGNAL ;
    PORT
      LAYER met2 ;
        RECT 888.810 0.000 889.090 4.000 ;
    END
  END tl_o[23]
  PIN tl_o[24]
    DIRECTION OUTPUT ;
    USE SIGNAL ;
    PORT
      LAYER met2 ;
        RECT 827.630 0.000 827.910 4.000 ;
    END
  END tl_o[24]
  PIN tl_o[25]
    DIRECTION OUTPUT ;
    USE SIGNAL ;
    PORT
      LAYER met3 ;
        RECT 1396.000 884.040 1400.000 884.640 ;
    END
  END tl_o[25]
  PIN tl_o[26]
    DIRECTION OUTPUT ;
    USE SIGNAL ;
    PORT
      LAYER met2 ;
        RECT 753.570 0.000 753.850 4.000 ;
    END
  END tl_o[26]
  PIN tl_o[27]
    DIRECTION OUTPUT ;
    USE SIGNAL ;
    PORT
      LAYER met3 ;
        RECT 1396.000 870.440 1400.000 871.040 ;
    END
  END tl_o[27]
  PIN tl_o[28]
    DIRECTION OUTPUT ;
    USE SIGNAL ;
    PORT
      LAYER met2 ;
        RECT 524.950 1396.000 525.230 1400.000 ;
    END
  END tl_o[28]
  PIN tl_o[29]
    DIRECTION OUTPUT ;
    USE SIGNAL ;
    PORT
      LAYER met2 ;
        RECT 563.590 1396.000 563.870 1400.000 ;
    END
  END tl_o[29]
  PIN tl_o[2]
    DIRECTION OUTPUT ;
    USE SIGNAL ;
    PORT
      LAYER met2 ;
        RECT 570.030 1396.000 570.310 1400.000 ;
    END
  END tl_o[2]
  PIN tl_o[30]
    DIRECTION OUTPUT ;
    USE SIGNAL ;
    PORT
      LAYER met3 ;
        RECT 1396.000 890.840 1400.000 891.440 ;
    END
  END tl_o[30]
  PIN tl_o[31]
    DIRECTION OUTPUT ;
    USE SIGNAL ;
    PORT
      LAYER met2 ;
        RECT 933.890 0.000 934.170 4.000 ;
    END
  END tl_o[31]
  PIN tl_o[32]
    DIRECTION OUTPUT ;
    USE SIGNAL ;
    PORT
      LAYER met2 ;
        RECT 676.290 1396.000 676.570 1400.000 ;
    END
  END tl_o[32]
  PIN tl_o[33]
    DIRECTION OUTPUT ;
    USE SIGNAL ;
    PORT
      LAYER met3 ;
        RECT 1396.000 867.040 1400.000 867.640 ;
    END
  END tl_o[33]
  PIN tl_o[34]
    DIRECTION OUTPUT ;
    USE SIGNAL ;
    PORT
      LAYER met2 ;
        RECT 843.730 0.000 844.010 4.000 ;
    END
  END tl_o[34]
  PIN tl_o[35]
    DIRECTION OUTPUT ;
    USE SIGNAL ;
    PORT
      LAYER met2 ;
        RECT 537.830 1396.000 538.110 1400.000 ;
    END
  END tl_o[35]
  PIN tl_o[36]
    DIRECTION OUTPUT ;
    USE SIGNAL ;
    PORT
      LAYER met2 ;
        RECT 489.530 1396.000 489.810 1400.000 ;
    END
  END tl_o[36]
  PIN tl_o[37]
    DIRECTION OUTPUT ;
    USE SIGNAL ;
    PORT
      LAYER met2 ;
        RECT 676.290 0.000 676.570 4.000 ;
    END
  END tl_o[37]
  PIN tl_o[38]
    DIRECTION OUTPUT ;
    USE SIGNAL ;
    PORT
      LAYER met2 ;
        RECT 486.310 1396.000 486.590 1400.000 ;
    END
  END tl_o[38]
  PIN tl_o[39]
    DIRECTION OUTPUT ;
    USE SIGNAL ;
    PORT
      LAYER met2 ;
        RECT 673.070 1396.000 673.350 1400.000 ;
    END
  END tl_o[39]
  PIN tl_o[3]
    DIRECTION OUTPUT ;
    USE SIGNAL ;
    PORT
      LAYER met3 ;
        RECT 0.000 540.640 4.000 541.240 ;
    END
  END tl_o[3]
  PIN tl_o[40]
    DIRECTION OUTPUT ;
    USE SIGNAL ;
    PORT
      LAYER met2 ;
        RECT 824.410 0.000 824.690 4.000 ;
    END
  END tl_o[40]
  PIN tl_o[41]
    DIRECTION OUTPUT ;
    USE SIGNAL ;
    PORT
      LAYER met2 ;
        RECT 930.670 0.000 930.950 4.000 ;
    END
  END tl_o[41]
  PIN tl_o[42]
    DIRECTION OUTPUT ;
    USE SIGNAL ;
    PORT
      LAYER met2 ;
        RECT 602.230 1396.000 602.510 1400.000 ;
    END
  END tl_o[42]
  PIN tl_o[43]
    DIRECTION OUTPUT ;
    USE SIGNAL ;
    PORT
      LAYER met2 ;
        RECT 470.210 1396.000 470.490 1400.000 ;
    END
  END tl_o[43]
  PIN tl_o[44]
    DIRECTION OUTPUT ;
    USE SIGNAL ;
    PORT
      LAYER met3 ;
        RECT 0.000 472.640 4.000 473.240 ;
    END
  END tl_o[44]
  PIN tl_o[45]
    DIRECTION OUTPUT ;
    USE SIGNAL ;
    PORT
      LAYER met3 ;
        RECT 0.000 520.240 4.000 520.840 ;
    END
  END tl_o[45]
  PIN tl_o[46]
    DIRECTION OUTPUT ;
    USE SIGNAL ;
    PORT
      LAYER met2 ;
        RECT 495.970 1396.000 496.250 1400.000 ;
    END
  END tl_o[46]
  PIN tl_o[47]
    DIRECTION OUTPUT ;
    USE SIGNAL ;
    PORT
      LAYER met3 ;
        RECT 1396.000 907.840 1400.000 908.440 ;
    END
  END tl_o[47]
  PIN tl_o[48]
    DIRECTION OUTPUT ;
    USE SIGNAL ;
    PORT
      LAYER met3 ;
        RECT 0.000 595.040 4.000 595.640 ;
    END
  END tl_o[48]
  PIN tl_o[49]
    DIRECTION OUTPUT ;
    USE SIGNAL ;
    PORT
      LAYER met2 ;
        RECT 721.370 0.000 721.650 4.000 ;
    END
  END tl_o[49]
  PIN tl_o[4]
    DIRECTION OUTPUT ;
    USE SIGNAL ;
    PORT
      LAYER met2 ;
        RECT 798.650 0.000 798.930 4.000 ;
    END
  END tl_o[4]
  PIN tl_o[50]
    DIRECTION OUTPUT ;
    USE SIGNAL ;
    PORT
      LAYER met3 ;
        RECT 1396.000 935.040 1400.000 935.640 ;
    END
  END tl_o[50]
  PIN tl_o[51]
    DIRECTION OUTPUT ;
    USE SIGNAL ;
    PORT
      LAYER met3 ;
        RECT 1396.000 775.240 1400.000 775.840 ;
    END
  END tl_o[51]
  PIN tl_o[52]
    DIRECTION OUTPUT ;
    USE SIGNAL ;
    PORT
      LAYER met2 ;
        RECT 547.490 1396.000 547.770 1400.000 ;
    END
  END tl_o[52]
  PIN tl_o[53]
    DIRECTION OUTPUT ;
    USE SIGNAL ;
    PORT
      LAYER met2 ;
        RECT 895.250 0.000 895.530 4.000 ;
    END
  END tl_o[53]
  PIN tl_o[54]
    DIRECTION OUTPUT ;
    USE SIGNAL ;
    PORT
      LAYER met3 ;
        RECT 1396.000 748.040 1400.000 748.640 ;
    END
  END tl_o[54]
  PIN tl_o[55]
    DIRECTION OUTPUT ;
    USE SIGNAL ;
    PORT
      LAYER met2 ;
        RECT 721.370 1396.000 721.650 1400.000 ;
    END
  END tl_o[55]
  PIN tl_o[56]
    DIRECTION OUTPUT ;
    USE SIGNAL ;
    PORT
      LAYER met2 ;
        RECT 911.350 0.000 911.630 4.000 ;
    END
  END tl_o[56]
  PIN tl_o[57]
    DIRECTION OUTPUT ;
    USE SIGNAL ;
    PORT
      LAYER met3 ;
        RECT 1396.000 819.440 1400.000 820.040 ;
    END
  END tl_o[57]
  PIN tl_o[58]
    DIRECTION OUTPUT ;
    USE SIGNAL ;
    PORT
      LAYER met3 ;
        RECT 0.000 499.840 4.000 500.440 ;
    END
  END tl_o[58]
  PIN tl_o[59]
    DIRECTION OUTPUT ;
    USE SIGNAL ;
    PORT
      LAYER met2 ;
        RECT 769.670 0.000 769.950 4.000 ;
    END
  END tl_o[59]
  PIN tl_o[5]
    DIRECTION OUTPUT ;
    USE SIGNAL ;
    PORT
      LAYER met3 ;
        RECT 1396.000 901.040 1400.000 901.640 ;
    END
  END tl_o[5]
  PIN tl_o[60]
    DIRECTION OUTPUT ;
    USE SIGNAL ;
    PORT
      LAYER met2 ;
        RECT 772.890 0.000 773.170 4.000 ;
    END
  END tl_o[60]
  PIN tl_o[61]
    DIRECTION OUTPUT ;
    USE SIGNAL ;
    PORT
      LAYER met2 ;
        RECT 869.490 0.000 869.770 4.000 ;
    END
  END tl_o[61]
  PIN tl_o[62]
    DIRECTION OUTPUT ;
    USE SIGNAL ;
    PORT
      LAYER met3 ;
        RECT 0.000 547.440 4.000 548.040 ;
    END
  END tl_o[62]
  PIN tl_o[63]
    DIRECTION OUTPUT ;
    USE SIGNAL ;
    ANTENNADIFFAREA 0.445500 ;
    PORT
      LAYER met3 ;
        RECT 0.000 646.040 4.000 646.640 ;
    END
  END tl_o[63]
  PIN tl_o[64]
    DIRECTION OUTPUT ;
    USE SIGNAL ;
    ANTENNADIFFAREA 0.445500 ;
    PORT
      LAYER met3 ;
        RECT 0.000 642.640 4.000 643.240 ;
    END
  END tl_o[64]
  PIN tl_o[65]
    DIRECTION OUTPUT ;
    USE SIGNAL ;
    ANTENNADIFFAREA 0.445500 ;
    PORT
      LAYER met3 ;
        RECT 0.000 639.240 4.000 639.840 ;
    END
  END tl_o[65]
  PIN tl_o[66]
    DIRECTION OUTPUT ;
    USE SIGNAL ;
    ANTENNADIFFAREA 0.445500 ;
    PORT
      LAYER met3 ;
        RECT 0.000 652.840 4.000 653.440 ;
    END
  END tl_o[66]
  PIN tl_o[67]
    DIRECTION OUTPUT ;
    USE SIGNAL ;
    ANTENNADIFFAREA 0.445500 ;
    PORT
      LAYER met3 ;
        RECT 0.000 666.440 4.000 667.040 ;
    END
  END tl_o[67]
  PIN tl_o[68]
    DIRECTION OUTPUT ;
    USE SIGNAL ;
    ANTENNADIFFAREA 0.445500 ;
    PORT
      LAYER met2 ;
        RECT 627.990 1396.000 628.270 1400.000 ;
    END
  END tl_o[68]
  PIN tl_o[69]
    DIRECTION OUTPUT ;
    USE SIGNAL ;
    ANTENNADIFFAREA 0.445500 ;
    PORT
      LAYER met2 ;
        RECT 615.110 1396.000 615.390 1400.000 ;
    END
  END tl_o[69]
  PIN tl_o[6]
    DIRECTION OUTPUT ;
    USE SIGNAL ;
    PORT
      LAYER met3 ;
        RECT 0.000 513.440 4.000 514.040 ;
    END
  END tl_o[6]
  PIN tl_o[70]
    DIRECTION OUTPUT ;
    USE SIGNAL ;
    ANTENNADIFFAREA 0.445500 ;
    PORT
      LAYER met2 ;
        RECT 631.210 1396.000 631.490 1400.000 ;
    END
  END tl_o[70]
  PIN tl_o[71]
    DIRECTION OUTPUT ;
    USE SIGNAL ;
    ANTENNADIFFAREA 0.445500 ;
    PORT
      LAYER met2 ;
        RECT 608.670 1396.000 608.950 1400.000 ;
    END
  END tl_o[71]
  PIN tl_o[72]
    DIRECTION OUTPUT ;
    USE SIGNAL ;
    ANTENNADIFFAREA 0.445500 ;
    PORT
      LAYER met2 ;
        RECT 621.550 1396.000 621.830 1400.000 ;
    END
  END tl_o[72]
  PIN tl_o[73]
    DIRECTION OUTPUT ;
    USE SIGNAL ;
    ANTENNADIFFAREA 0.445500 ;
    PORT
      LAYER met2 ;
        RECT 618.330 1396.000 618.610 1400.000 ;
    END
  END tl_o[73]
  PIN tl_o[74]
    DIRECTION OUTPUT ;
    USE SIGNAL ;
    ANTENNADIFFAREA 0.445500 ;
    PORT
      LAYER met2 ;
        RECT 611.890 1396.000 612.170 1400.000 ;
    END
  END tl_o[74]
  PIN tl_o[75]
    DIRECTION OUTPUT ;
    USE SIGNAL ;
    ANTENNADIFFAREA 0.445500 ;
    PORT
      LAYER met2 ;
        RECT 624.770 1396.000 625.050 1400.000 ;
    END
  END tl_o[75]
  PIN tl_o[76]
    DIRECTION OUTPUT ;
    USE SIGNAL ;
    ANTENNADIFFAREA 0.445500 ;
    PORT
      LAYER met2 ;
        RECT 673.070 0.000 673.350 4.000 ;
    END
  END tl_o[76]
  PIN tl_o[77]
    DIRECTION OUTPUT ;
    USE SIGNAL ;
    ANTENNADIFFAREA 0.445500 ;
    PORT
      LAYER met3 ;
        RECT 0.000 669.840 4.000 670.440 ;
    END
  END tl_o[77]
  PIN tl_o[78]
    DIRECTION OUTPUT ;
    USE SIGNAL ;
    ANTENNADIFFAREA 0.445500 ;
    PORT
      LAYER met2 ;
        RECT 660.190 1396.000 660.470 1400.000 ;
    END
  END tl_o[78]
  PIN tl_o[79]
    DIRECTION OUTPUT ;
    USE SIGNAL ;
    ANTENNADIFFAREA 0.445500 ;
    PORT
      LAYER met2 ;
        RECT 724.590 0.000 724.870 4.000 ;
    END
  END tl_o[79]
  PIN tl_o[7]
    DIRECTION OUTPUT ;
    USE SIGNAL ;
    PORT
      LAYER met3 ;
        RECT 1396.000 904.440 1400.000 905.040 ;
    END
  END tl_o[7]
  PIN tl_o[80]
    DIRECTION OUTPUT ;
    USE SIGNAL ;
    ANTENNADIFFAREA 0.445500 ;
    PORT
      LAYER met2 ;
        RECT 750.350 0.000 750.630 4.000 ;
    END
  END tl_o[80]
  PIN tl_o[81]
    DIRECTION OUTPUT ;
    USE SIGNAL ;
    ANTENNADIFFAREA 0.445500 ;
    PORT
      LAYER met2 ;
        RECT 740.690 0.000 740.970 4.000 ;
    END
  END tl_o[81]
  PIN tl_o[82]
    DIRECTION OUTPUT ;
    USE SIGNAL ;
    ANTENNADIFFAREA 0.445500 ;
    PORT
      LAYER met2 ;
        RECT 760.010 0.000 760.290 4.000 ;
    END
  END tl_o[82]
  PIN tl_o[83]
    DIRECTION OUTPUT ;
    USE SIGNAL ;
    ANTENNADIFFAREA 0.445500 ;
    PORT
      LAYER met2 ;
        RECT 669.850 1396.000 670.130 1400.000 ;
    END
  END tl_o[83]
  PIN tl_o[84]
    DIRECTION OUTPUT ;
    USE SIGNAL ;
    ANTENNADIFFAREA 0.445500 ;
    PORT
      LAYER met2 ;
        RECT 766.450 0.000 766.730 4.000 ;
    END
  END tl_o[84]
  PIN tl_o[85]
    DIRECTION OUTPUT ;
    USE SIGNAL ;
    ANTENNADIFFAREA 0.445500 ;
    PORT
      LAYER met2 ;
        RECT 763.230 0.000 763.510 4.000 ;
    END
  END tl_o[85]
  PIN tl_o[86]
    DIRECTION OUTPUT ;
    USE SIGNAL ;
    ANTENNADIFFAREA 0.445500 ;
    PORT
      LAYER met3 ;
        RECT 1396.000 744.640 1400.000 745.240 ;
    END
  END tl_o[86]
  PIN tl_o[87]
    DIRECTION OUTPUT ;
    USE SIGNAL ;
    ANTENNADIFFAREA 0.445500 ;
    PORT
      LAYER met3 ;
        RECT 1396.000 751.440 1400.000 752.040 ;
    END
  END tl_o[87]
  PIN tl_o[88]
    DIRECTION OUTPUT ;
    USE SIGNAL ;
    ANTENNADIFFAREA 0.445500 ;
    PORT
      LAYER met3 ;
        RECT 1396.000 782.040 1400.000 782.640 ;
    END
  END tl_o[88]
  PIN tl_o[89]
    DIRECTION OUTPUT ;
    USE SIGNAL ;
    ANTENNADIFFAREA 0.445500 ;
    PORT
      LAYER met3 ;
        RECT 1396.000 754.840 1400.000 755.440 ;
    END
  END tl_o[89]
  PIN tl_o[8]
    DIRECTION OUTPUT ;
    USE SIGNAL ;
    ANTENNADIFFAREA 0.445500 ;
    PORT
      LAYER met2 ;
        RECT 653.750 1396.000 654.030 1400.000 ;
    END
  END tl_o[8]
  PIN tl_o[90]
    DIRECTION OUTPUT ;
    USE SIGNAL ;
    ANTENNADIFFAREA 0.445500 ;
    PORT
      LAYER met3 ;
        RECT 1396.000 731.040 1400.000 731.640 ;
    END
  END tl_o[90]
  PIN tl_o[91]
    DIRECTION OUTPUT ;
    USE SIGNAL ;
    ANTENNADIFFAREA 0.445500 ;
    PORT
      LAYER met3 ;
        RECT 1396.000 778.640 1400.000 779.240 ;
    END
  END tl_o[91]
  PIN tl_o[92]
    DIRECTION OUTPUT ;
    USE SIGNAL ;
    ANTENNADIFFAREA 0.445500 ;
    PORT
      LAYER met2 ;
        RECT 714.930 1396.000 715.210 1400.000 ;
    END
  END tl_o[92]
  PIN tl_o[93]
    DIRECTION OUTPUT ;
    USE SIGNAL ;
    PORT
      LAYER met3 ;
        RECT 1396.000 863.640 1400.000 864.240 ;
    END
  END tl_o[93]
  PIN tl_o[94]
    DIRECTION OUTPUT ;
    USE SIGNAL ;
    PORT
      LAYER met2 ;
        RECT 776.110 0.000 776.390 4.000 ;
    END
  END tl_o[94]
  PIN tl_o[95]
    DIRECTION OUTPUT ;
    USE SIGNAL ;
    PORT
      LAYER met3 ;
        RECT 1396.000 843.240 1400.000 843.840 ;
    END
  END tl_o[95]
  PIN tl_o[96]
    DIRECTION OUTPUT ;
    USE SIGNAL ;
    PORT
      LAYER met3 ;
        RECT 1396.000 829.640 1400.000 830.240 ;
    END
  END tl_o[96]
  PIN tl_o[97]
    DIRECTION OUTPUT ;
    USE SIGNAL ;
    PORT
      LAYER met2 ;
        RECT 685.950 0.000 686.230 4.000 ;
    END
  END tl_o[97]
  PIN tl_o[98]
    DIRECTION OUTPUT ;
    USE SIGNAL ;
    PORT
      LAYER met2 ;
        RECT 892.030 0.000 892.310 4.000 ;
    END
  END tl_o[98]
  PIN tl_o[99]
    DIRECTION OUTPUT ;
    USE SIGNAL ;
    PORT
      LAYER met2 ;
        RECT 499.190 1396.000 499.470 1400.000 ;
    END
  END tl_o[99]
  PIN tl_o[9]
    DIRECTION OUTPUT ;
    USE SIGNAL ;
    ANTENNADIFFAREA 0.445500 ;
    PORT
      LAYER met2 ;
        RECT 666.630 1396.000 666.910 1400.000 ;
    END
  END tl_o[9]
  OBS
      LAYER nwell ;
        RECT 5.330 10.795 1394.450 1387.285 ;
      LAYER li1 ;
        RECT 5.520 10.795 1394.260 1387.285 ;
      LAYER met1 ;
        RECT 4.210 10.640 1394.260 1387.440 ;
      LAYER met2 ;
        RECT 4.230 1395.720 469.930 1396.000 ;
        RECT 470.770 1395.720 482.810 1396.000 ;
        RECT 483.650 1395.720 486.030 1396.000 ;
        RECT 486.870 1395.720 489.250 1396.000 ;
        RECT 490.090 1395.720 492.470 1396.000 ;
        RECT 493.310 1395.720 495.690 1396.000 ;
        RECT 496.530 1395.720 498.910 1396.000 ;
        RECT 499.750 1395.720 524.670 1396.000 ;
        RECT 525.510 1395.720 537.550 1396.000 ;
        RECT 538.390 1395.720 547.210 1396.000 ;
        RECT 548.050 1395.720 563.310 1396.000 ;
        RECT 564.150 1395.720 569.750 1396.000 ;
        RECT 570.590 1395.720 579.410 1396.000 ;
        RECT 580.250 1395.720 601.950 1396.000 ;
        RECT 602.790 1395.720 608.390 1396.000 ;
        RECT 609.230 1395.720 611.610 1396.000 ;
        RECT 612.450 1395.720 614.830 1396.000 ;
        RECT 615.670 1395.720 618.050 1396.000 ;
        RECT 618.890 1395.720 621.270 1396.000 ;
        RECT 622.110 1395.720 624.490 1396.000 ;
        RECT 625.330 1395.720 627.710 1396.000 ;
        RECT 628.550 1395.720 630.930 1396.000 ;
        RECT 631.770 1395.720 653.470 1396.000 ;
        RECT 654.310 1395.720 659.910 1396.000 ;
        RECT 660.750 1395.720 666.350 1396.000 ;
        RECT 667.190 1395.720 669.570 1396.000 ;
        RECT 670.410 1395.720 672.790 1396.000 ;
        RECT 673.630 1395.720 676.010 1396.000 ;
        RECT 676.850 1395.720 682.450 1396.000 ;
        RECT 683.290 1395.720 685.670 1396.000 ;
        RECT 686.510 1395.720 695.330 1396.000 ;
        RECT 696.170 1395.720 711.430 1396.000 ;
        RECT 712.270 1395.720 714.650 1396.000 ;
        RECT 715.490 1395.720 717.870 1396.000 ;
        RECT 718.710 1395.720 721.090 1396.000 ;
        RECT 721.930 1395.720 1392.330 1396.000 ;
        RECT 4.230 4.280 1392.330 1395.720 ;
        RECT 4.230 4.000 6.250 4.280 ;
        RECT 7.090 4.000 9.470 4.280 ;
        RECT 10.310 4.000 12.690 4.280 ;
        RECT 13.530 4.000 15.910 4.280 ;
        RECT 16.750 4.000 19.130 4.280 ;
        RECT 19.970 4.000 22.350 4.280 ;
        RECT 23.190 4.000 25.570 4.280 ;
        RECT 26.410 4.000 28.790 4.280 ;
        RECT 29.630 4.000 32.010 4.280 ;
        RECT 32.850 4.000 35.230 4.280 ;
        RECT 36.070 4.000 38.450 4.280 ;
        RECT 39.290 4.000 41.670 4.280 ;
        RECT 42.510 4.000 44.890 4.280 ;
        RECT 45.730 4.000 48.110 4.280 ;
        RECT 48.950 4.000 51.330 4.280 ;
        RECT 52.170 4.000 54.550 4.280 ;
        RECT 55.390 4.000 57.770 4.280 ;
        RECT 58.610 4.000 60.990 4.280 ;
        RECT 61.830 4.000 64.210 4.280 ;
        RECT 65.050 4.000 67.430 4.280 ;
        RECT 68.270 4.000 70.650 4.280 ;
        RECT 71.490 4.000 73.870 4.280 ;
        RECT 74.710 4.000 77.090 4.280 ;
        RECT 77.930 4.000 80.310 4.280 ;
        RECT 81.150 4.000 83.530 4.280 ;
        RECT 84.370 4.000 86.750 4.280 ;
        RECT 87.590 4.000 89.970 4.280 ;
        RECT 90.810 4.000 93.190 4.280 ;
        RECT 94.030 4.000 96.410 4.280 ;
        RECT 97.250 4.000 99.630 4.280 ;
        RECT 100.470 4.000 102.850 4.280 ;
        RECT 103.690 4.000 106.070 4.280 ;
        RECT 106.910 4.000 109.290 4.280 ;
        RECT 110.130 4.000 112.510 4.280 ;
        RECT 113.350 4.000 115.730 4.280 ;
        RECT 116.570 4.000 118.950 4.280 ;
        RECT 119.790 4.000 122.170 4.280 ;
        RECT 123.010 4.000 125.390 4.280 ;
        RECT 126.230 4.000 128.610 4.280 ;
        RECT 129.450 4.000 131.830 4.280 ;
        RECT 132.670 4.000 135.050 4.280 ;
        RECT 135.890 4.000 138.270 4.280 ;
        RECT 139.110 4.000 141.490 4.280 ;
        RECT 142.330 4.000 144.710 4.280 ;
        RECT 145.550 4.000 147.930 4.280 ;
        RECT 148.770 4.000 151.150 4.280 ;
        RECT 151.990 4.000 154.370 4.280 ;
        RECT 155.210 4.000 157.590 4.280 ;
        RECT 158.430 4.000 160.810 4.280 ;
        RECT 161.650 4.000 164.030 4.280 ;
        RECT 164.870 4.000 167.250 4.280 ;
        RECT 168.090 4.000 170.470 4.280 ;
        RECT 171.310 4.000 173.690 4.280 ;
        RECT 174.530 4.000 176.910 4.280 ;
        RECT 177.750 4.000 180.130 4.280 ;
        RECT 180.970 4.000 183.350 4.280 ;
        RECT 184.190 4.000 186.570 4.280 ;
        RECT 187.410 4.000 189.790 4.280 ;
        RECT 190.630 4.000 193.010 4.280 ;
        RECT 193.850 4.000 196.230 4.280 ;
        RECT 197.070 4.000 199.450 4.280 ;
        RECT 200.290 4.000 202.670 4.280 ;
        RECT 203.510 4.000 205.890 4.280 ;
        RECT 206.730 4.000 209.110 4.280 ;
        RECT 209.950 4.000 212.330 4.280 ;
        RECT 213.170 4.000 215.550 4.280 ;
        RECT 216.390 4.000 218.770 4.280 ;
        RECT 219.610 4.000 221.990 4.280 ;
        RECT 222.830 4.000 225.210 4.280 ;
        RECT 226.050 4.000 228.430 4.280 ;
        RECT 229.270 4.000 231.650 4.280 ;
        RECT 232.490 4.000 234.870 4.280 ;
        RECT 235.710 4.000 238.090 4.280 ;
        RECT 238.930 4.000 241.310 4.280 ;
        RECT 242.150 4.000 244.530 4.280 ;
        RECT 245.370 4.000 247.750 4.280 ;
        RECT 248.590 4.000 250.970 4.280 ;
        RECT 251.810 4.000 254.190 4.280 ;
        RECT 255.030 4.000 257.410 4.280 ;
        RECT 258.250 4.000 260.630 4.280 ;
        RECT 261.470 4.000 263.850 4.280 ;
        RECT 264.690 4.000 267.070 4.280 ;
        RECT 267.910 4.000 270.290 4.280 ;
        RECT 271.130 4.000 273.510 4.280 ;
        RECT 274.350 4.000 276.730 4.280 ;
        RECT 277.570 4.000 279.950 4.280 ;
        RECT 280.790 4.000 283.170 4.280 ;
        RECT 284.010 4.000 286.390 4.280 ;
        RECT 287.230 4.000 289.610 4.280 ;
        RECT 290.450 4.000 292.830 4.280 ;
        RECT 293.670 4.000 296.050 4.280 ;
        RECT 296.890 4.000 299.270 4.280 ;
        RECT 300.110 4.000 302.490 4.280 ;
        RECT 303.330 4.000 305.710 4.280 ;
        RECT 306.550 4.000 308.930 4.280 ;
        RECT 309.770 4.000 312.150 4.280 ;
        RECT 312.990 4.000 315.370 4.280 ;
        RECT 316.210 4.000 318.590 4.280 ;
        RECT 319.430 4.000 321.810 4.280 ;
        RECT 322.650 4.000 325.030 4.280 ;
        RECT 325.870 4.000 328.250 4.280 ;
        RECT 329.090 4.000 331.470 4.280 ;
        RECT 332.310 4.000 334.690 4.280 ;
        RECT 335.530 4.000 337.910 4.280 ;
        RECT 338.750 4.000 341.130 4.280 ;
        RECT 341.970 4.000 344.350 4.280 ;
        RECT 345.190 4.000 347.570 4.280 ;
        RECT 348.410 4.000 350.790 4.280 ;
        RECT 351.630 4.000 354.010 4.280 ;
        RECT 354.850 4.000 357.230 4.280 ;
        RECT 358.070 4.000 360.450 4.280 ;
        RECT 361.290 4.000 363.670 4.280 ;
        RECT 364.510 4.000 366.890 4.280 ;
        RECT 367.730 4.000 370.110 4.280 ;
        RECT 370.950 4.000 373.330 4.280 ;
        RECT 374.170 4.000 376.550 4.280 ;
        RECT 377.390 4.000 643.810 4.280 ;
        RECT 644.650 4.000 672.790 4.280 ;
        RECT 673.630 4.000 676.010 4.280 ;
        RECT 676.850 4.000 679.230 4.280 ;
        RECT 680.070 4.000 682.450 4.280 ;
        RECT 683.290 4.000 685.670 4.280 ;
        RECT 686.510 4.000 688.890 4.280 ;
        RECT 689.730 4.000 692.110 4.280 ;
        RECT 692.950 4.000 695.330 4.280 ;
        RECT 696.170 4.000 698.550 4.280 ;
        RECT 699.390 4.000 701.770 4.280 ;
        RECT 702.610 4.000 704.990 4.280 ;
        RECT 705.830 4.000 708.210 4.280 ;
        RECT 709.050 4.000 711.430 4.280 ;
        RECT 712.270 4.000 714.650 4.280 ;
        RECT 715.490 4.000 717.870 4.280 ;
        RECT 718.710 4.000 721.090 4.280 ;
        RECT 721.930 4.000 724.310 4.280 ;
        RECT 725.150 4.000 727.530 4.280 ;
        RECT 728.370 4.000 730.750 4.280 ;
        RECT 731.590 4.000 733.970 4.280 ;
        RECT 734.810 4.000 737.190 4.280 ;
        RECT 738.030 4.000 740.410 4.280 ;
        RECT 741.250 4.000 743.630 4.280 ;
        RECT 744.470 4.000 746.850 4.280 ;
        RECT 747.690 4.000 750.070 4.280 ;
        RECT 750.910 4.000 753.290 4.280 ;
        RECT 754.130 4.000 756.510 4.280 ;
        RECT 757.350 4.000 759.730 4.280 ;
        RECT 760.570 4.000 762.950 4.280 ;
        RECT 763.790 4.000 766.170 4.280 ;
        RECT 767.010 4.000 769.390 4.280 ;
        RECT 770.230 4.000 772.610 4.280 ;
        RECT 773.450 4.000 775.830 4.280 ;
        RECT 776.670 4.000 779.050 4.280 ;
        RECT 779.890 4.000 782.270 4.280 ;
        RECT 783.110 4.000 798.370 4.280 ;
        RECT 799.210 4.000 824.130 4.280 ;
        RECT 824.970 4.000 827.350 4.280 ;
        RECT 828.190 4.000 843.450 4.280 ;
        RECT 844.290 4.000 849.890 4.280 ;
        RECT 850.730 4.000 853.110 4.280 ;
        RECT 853.950 4.000 869.210 4.280 ;
        RECT 870.050 4.000 888.530 4.280 ;
        RECT 889.370 4.000 891.750 4.280 ;
        RECT 892.590 4.000 894.970 4.280 ;
        RECT 895.810 4.000 898.190 4.280 ;
        RECT 899.030 4.000 901.410 4.280 ;
        RECT 902.250 4.000 907.850 4.280 ;
        RECT 908.690 4.000 911.070 4.280 ;
        RECT 911.910 4.000 914.290 4.280 ;
        RECT 915.130 4.000 930.390 4.280 ;
        RECT 931.230 4.000 933.610 4.280 ;
        RECT 934.450 4.000 1392.330 4.280 ;
      LAYER met3 ;
        RECT 3.990 936.040 1396.000 1387.365 ;
        RECT 3.990 934.640 1395.600 936.040 ;
        RECT 3.990 919.040 1396.000 934.640 ;
        RECT 3.990 917.640 1395.600 919.040 ;
        RECT 3.990 908.840 1396.000 917.640 ;
        RECT 3.990 907.440 1395.600 908.840 ;
        RECT 3.990 905.440 1396.000 907.440 ;
        RECT 3.990 904.040 1395.600 905.440 ;
        RECT 3.990 902.040 1396.000 904.040 ;
        RECT 3.990 900.640 1395.600 902.040 ;
        RECT 3.990 891.840 1396.000 900.640 ;
        RECT 3.990 890.440 1395.600 891.840 ;
        RECT 3.990 885.040 1396.000 890.440 ;
        RECT 3.990 883.640 1395.600 885.040 ;
        RECT 3.990 874.840 1396.000 883.640 ;
        RECT 3.990 873.440 1395.600 874.840 ;
        RECT 3.990 871.440 1396.000 873.440 ;
        RECT 3.990 870.040 1395.600 871.440 ;
        RECT 3.990 868.040 1396.000 870.040 ;
        RECT 3.990 866.640 1395.600 868.040 ;
        RECT 3.990 864.640 1396.000 866.640 ;
        RECT 3.990 863.240 1395.600 864.640 ;
        RECT 3.990 861.240 1396.000 863.240 ;
        RECT 3.990 859.840 1395.600 861.240 ;
        RECT 3.990 844.240 1396.000 859.840 ;
        RECT 3.990 842.840 1395.600 844.240 ;
        RECT 3.990 830.640 1396.000 842.840 ;
        RECT 3.990 829.240 1395.600 830.640 ;
        RECT 3.990 820.440 1396.000 829.240 ;
        RECT 3.990 819.040 1395.600 820.440 ;
        RECT 3.990 783.040 1396.000 819.040 ;
        RECT 3.990 781.640 1395.600 783.040 ;
        RECT 3.990 779.640 1396.000 781.640 ;
        RECT 3.990 778.240 1395.600 779.640 ;
        RECT 3.990 776.240 1396.000 778.240 ;
        RECT 3.990 774.840 1395.600 776.240 ;
        RECT 3.990 755.840 1396.000 774.840 ;
        RECT 3.990 754.440 1395.600 755.840 ;
        RECT 3.990 752.440 1396.000 754.440 ;
        RECT 3.990 751.040 1395.600 752.440 ;
        RECT 3.990 749.040 1396.000 751.040 ;
        RECT 3.990 747.640 1395.600 749.040 ;
        RECT 3.990 745.640 1396.000 747.640 ;
        RECT 3.990 744.240 1395.600 745.640 ;
        RECT 3.990 732.040 1396.000 744.240 ;
        RECT 3.990 730.640 1395.600 732.040 ;
        RECT 3.990 670.840 1396.000 730.640 ;
        RECT 4.400 669.440 1396.000 670.840 ;
        RECT 3.990 667.440 1396.000 669.440 ;
        RECT 4.400 666.040 1396.000 667.440 ;
        RECT 3.990 653.840 1396.000 666.040 ;
        RECT 4.400 652.440 1396.000 653.840 ;
        RECT 3.990 647.040 1396.000 652.440 ;
        RECT 4.400 645.640 1396.000 647.040 ;
        RECT 3.990 643.640 1396.000 645.640 ;
        RECT 4.400 642.240 1396.000 643.640 ;
        RECT 3.990 640.240 1396.000 642.240 ;
        RECT 4.400 638.840 1396.000 640.240 ;
        RECT 3.990 609.640 1396.000 638.840 ;
        RECT 4.400 608.240 1396.000 609.640 ;
        RECT 3.990 596.040 1396.000 608.240 ;
        RECT 4.400 594.640 1396.000 596.040 ;
        RECT 3.990 548.440 1396.000 594.640 ;
        RECT 4.400 547.040 1396.000 548.440 ;
        RECT 3.990 545.040 1396.000 547.040 ;
        RECT 4.400 543.640 1396.000 545.040 ;
        RECT 3.990 541.640 1396.000 543.640 ;
        RECT 4.400 540.240 1396.000 541.640 ;
        RECT 3.990 528.040 1396.000 540.240 ;
        RECT 4.400 526.640 1396.000 528.040 ;
        RECT 3.990 521.240 1396.000 526.640 ;
        RECT 4.400 519.840 1396.000 521.240 ;
        RECT 3.990 514.440 1396.000 519.840 ;
        RECT 4.400 513.040 1396.000 514.440 ;
        RECT 3.990 507.640 1396.000 513.040 ;
        RECT 4.400 506.240 1396.000 507.640 ;
        RECT 3.990 500.840 1396.000 506.240 ;
        RECT 4.400 499.440 1396.000 500.840 ;
        RECT 3.990 473.640 1396.000 499.440 ;
        RECT 4.400 472.240 1396.000 473.640 ;
        RECT 3.990 10.715 1396.000 472.240 ;
      LAYER met4 ;
        RECT 647.055 655.695 746.745 775.705 ;
  END
END rv_core_ibex_tlul
END LIBRARY

